VERSION 5.8 ;
BUSBITCHARS "[]" ;
DIVIDERCHAR "/" ;
UNITS
    DATABASE MICRONS 1000 ;
END UNITS

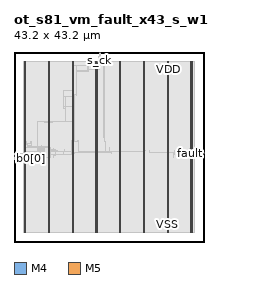
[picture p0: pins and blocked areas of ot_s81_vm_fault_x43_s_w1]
MACRO ot_s81_vm_fault_x43_s_w1
  FOREIGN ot_s81_vm_fault_x43_s_w1 0 0 ;
  CLASS BLOCK ;
  SIZE 43.2 BY 43.2 ;
  PIN b0[0]
    DIRECTION INPUT ;
    USE SIGNAL ;
    PORT
      LAYER M4 ;
        RECT  0 19.056 0.084 19.08 ;
    END
  END b0[0]
  PIN b0[1]
    DIRECTION INPUT ;
    USE SIGNAL ;
    PORT
      LAYER M4 ;
        RECT  0 19.152 0.084 19.176 ;
    END
  END b0[1]
  PIN b2[0]
    DIRECTION INPUT ;
    USE SIGNAL ;
    PORT
      LAYER M4 ;
        RECT  0 19.248 0.084 19.272 ;
    END
  END b2[0]
  PIN b2[1]
    DIRECTION INPUT ;
    USE SIGNAL ;
    PORT
      LAYER M4 ;
        RECT  0 19.344 0.084 19.368 ;
    END
  END b2[1]
  PIN b3[0]
    DIRECTION INPUT ;
    USE SIGNAL ;
    PORT
      LAYER M4 ;
        RECT  0 19.44 0.084 19.464 ;
    END
  END b3[0]
  PIN b3[1]
    DIRECTION INPUT ;
    USE SIGNAL ;
    PORT
      LAYER M4 ;
        RECT  0 19.536 0.084 19.56 ;
    END
  END b3[1]
  PIN bpar[0]
    DIRECTION INPUT ;
    USE SIGNAL ;
    PORT
      LAYER M4 ;
        RECT  0 19.632 0.084 19.656 ;
    END
  END bpar[0]
  PIN bpar[1]
    DIRECTION INPUT ;
    USE SIGNAL ;
    PORT
      LAYER M4 ;
        RECT  0 19.728 0.084 19.752 ;
    END
  END bpar[1]
  PIN bpar[2]
    DIRECTION INPUT ;
    USE SIGNAL ;
    PORT
      LAYER M4 ;
        RECT  0 19.824 0.084 19.848 ;
    END
  END bpar[2]
  PIN fault
    DIRECTION OUTPUT ;
    USE SIGNAL ;
    PORT
      LAYER M4 ;
        RECT  43.116 20.208 43.2 20.232 ;
    END
  END fault
  PIN o_d
    DIRECTION OUTPUT ;
    USE SIGNAL ;
    PORT
      LAYER M4 ;
        RECT  43.116 20.304 43.2 20.328 ;
    END
  END o_d
  PIN o_v
    DIRECTION OUTPUT ;
    USE SIGNAL ;
    PORT
      LAYER M4 ;
        RECT  43.116 20.4 43.2 20.424 ;
    END
  END o_v
  PIN ph1_bad
    DIRECTION INPUT ;
    USE SIGNAL ;
    PORT
      LAYER M4 ;
        RECT  0 19.92 0.084 19.944 ;
    END
  END ph1_bad
  PIN s_ck
    DIRECTION INPUT ;
    USE SIGNAL ;
    PORT
      LAYER M5 ;
        RECT  19.44 43.116 19.464 43.2 ;
    END
  END s_ck
  PIN s_rst_n
    DIRECTION INPUT ;
    USE SIGNAL ;
    PORT
      LAYER M5 ;
        RECT  19.536 43.116 19.56 43.2 ;
    END
  END s_rst_n
  PIN t_mark
    DIRECTION INPUT ;
    USE SIGNAL ;
    PORT
      LAYER M4 ;
        RECT  0 20.016 0.084 20.04 ;
    END
  END t_mark
  PIN VDD
    DIRECTION INOUT ;
    USE POWER ;
    PORT
      LAYER M5 ;
        RECT  40.392 2.151 40.512 41.049 ;
        RECT  34.992 2.151 35.112 41.049 ;
        RECT  29.592 2.151 29.712 41.049 ;
        RECT  24.192 2.151 24.312 41.049 ;
        RECT  18.792 2.151 18.912 41.049 ;
        RECT  13.392 2.151 13.512 41.049 ;
        RECT  7.992 2.151 8.112 41.049 ;
        RECT  2.592 2.151 2.712 41.049 ;
    END
  END VDD
  PIN VSS
    DIRECTION INOUT ;
    USE GROUND ;
    PORT
      LAYER M5 ;
        RECT  40.2 2.137 40.32 41.063 ;
        RECT  34.8 2.137 34.92 41.063 ;
        RECT  29.4 2.137 29.52 41.063 ;
        RECT  24 2.137 24.12 41.063 ;
        RECT  18.6 2.137 18.72 41.063 ;
        RECT  13.2 2.137 13.32 41.063 ;
        RECT  7.8 2.137 7.92 41.063 ;
        RECT  2.4 2.137 2.52 41.063 ;
    END
  END VSS
  # OT_OBS_CLOSED layer=M5 d_um=1.536 added=3
  OBS
    LAYER RVTN ;
     RECT  2.16 2.16 41.04 2.295 ;
     RECT  2.16 2.565 41.04 2.835 ;
     RECT  2.16 3.105 41.04 3.375 ;
     RECT  2.16 3.645 41.04 3.915 ;
     RECT  2.16 4.185 41.04 4.455 ;
     RECT  2.16 4.725 41.04 4.995 ;
     RECT  2.16 5.265 41.04 5.535 ;
     RECT  2.16 5.805 41.04 6.075 ;
     RECT  2.16 6.345 41.04 6.615 ;
     RECT  2.16 6.885 41.04 7.155 ;
     RECT  2.16 7.425 41.04 7.695 ;
     RECT  2.16 7.965 41.04 8.235 ;
     RECT  2.16 8.505 41.04 8.775 ;
     RECT  2.16 9.045 41.04 9.315 ;
     RECT  2.16 9.585 41.04 9.855 ;
     RECT  2.16 10.125 41.04 10.395 ;
     RECT  2.16 10.665 41.04 10.935 ;
     RECT  2.16 11.205 41.04 11.475 ;
     RECT  2.16 11.745 41.04 12.015 ;
     RECT  2.16 12.285 41.04 12.555 ;
     RECT  2.16 12.825 41.04 13.095 ;
     RECT  2.16 13.365 41.04 13.635 ;
     RECT  2.16 13.905 41.04 14.175 ;
     RECT  2.16 14.445 41.04 14.715 ;
     RECT  2.16 14.985 41.04 15.255 ;
     RECT  2.16 15.525 41.04 15.795 ;
     RECT  2.16 16.065 41.04 16.335 ;
     RECT  2.16 16.605 41.04 16.875 ;
     RECT  2.16 17.145 41.04 17.415 ;
     RECT  2.16 17.685 41.04 17.955 ;
     RECT  2.16 18.225 41.04 18.495 ;
     RECT  2.16 18.765 41.04 19.035 ;
     RECT  2.16 19.305 41.04 19.575 ;
     RECT  2.16 19.845 41.04 20.115 ;
     RECT  2.16 20.385 41.04 20.655 ;
     RECT  2.16 20.925 41.04 21.195 ;
     RECT  2.16 21.465 41.04 21.735 ;
     RECT  2.16 22.005 41.04 22.275 ;
     RECT  2.16 22.545 41.04 22.815 ;
     RECT  2.16 23.085 41.04 23.355 ;
     RECT  2.16 23.625 41.04 23.895 ;
     RECT  2.16 24.165 41.04 24.435 ;
     RECT  2.16 24.705 41.04 24.975 ;
     RECT  2.16 25.245 41.04 25.515 ;
     RECT  2.16 25.785 41.04 26.055 ;
     RECT  2.16 26.325 41.04 26.595 ;
     RECT  2.16 26.865 41.04 27.135 ;
     RECT  2.16 27.405 41.04 27.675 ;
     RECT  2.16 27.945 41.04 28.215 ;
     RECT  2.16 28.485 41.04 28.755 ;
     RECT  2.16 29.025 41.04 29.295 ;
     RECT  2.16 29.565 41.04 29.835 ;
     RECT  2.16 30.105 41.04 30.375 ;
     RECT  2.16 30.645 41.04 30.915 ;
     RECT  2.16 31.185 41.04 31.455 ;
     RECT  2.16 31.725 41.04 31.995 ;
     RECT  2.16 32.265 41.04 32.535 ;
     RECT  2.16 32.805 41.04 33.075 ;
     RECT  2.16 33.345 41.04 33.615 ;
     RECT  2.16 33.885 41.04 34.155 ;
     RECT  2.16 34.425 41.04 34.695 ;
     RECT  2.16 34.965 41.04 35.235 ;
     RECT  2.16 35.505 41.04 35.775 ;
     RECT  2.16 36.045 41.04 36.315 ;
     RECT  2.16 36.585 41.04 36.855 ;
     RECT  2.16 37.125 41.04 37.395 ;
     RECT  2.16 37.665 41.04 37.935 ;
     RECT  2.16 38.205 41.04 38.475 ;
     RECT  2.16 38.745 41.04 39.015 ;
     RECT  2.16 39.285 41.04 39.555 ;
     RECT  2.16 39.825 41.04 40.095 ;
     RECT  2.16 40.365 41.04 40.635 ;
     RECT  2.16 40.905 41.04 41.04 ;
    LAYER RVTP ;
     RECT  2.16 2.295 41.04 2.565 ;
     RECT  2.16 2.835 41.04 3.105 ;
     RECT  2.16 3.375 41.04 3.645 ;
     RECT  2.16 3.915 41.04 4.185 ;
     RECT  2.16 4.455 41.04 4.725 ;
     RECT  2.16 4.995 41.04 5.265 ;
     RECT  2.16 5.535 41.04 5.805 ;
     RECT  2.16 6.075 41.04 6.345 ;
     RECT  2.16 6.615 41.04 6.885 ;
     RECT  2.16 7.155 41.04 7.425 ;
     RECT  2.16 7.695 41.04 7.965 ;
     RECT  2.16 8.235 41.04 8.505 ;
     RECT  2.16 8.775 41.04 9.045 ;
     RECT  2.16 9.315 41.04 9.585 ;
     RECT  2.16 9.855 41.04 10.125 ;
     RECT  2.16 10.395 41.04 10.665 ;
     RECT  2.16 10.935 41.04 11.205 ;
     RECT  2.16 11.475 41.04 11.745 ;
     RECT  2.16 12.015 41.04 12.285 ;
     RECT  2.16 12.555 41.04 12.825 ;
     RECT  2.16 13.095 41.04 13.365 ;
     RECT  2.16 13.635 41.04 13.905 ;
     RECT  2.16 14.175 41.04 14.445 ;
     RECT  2.16 14.715 41.04 14.985 ;
     RECT  2.16 15.255 41.04 15.525 ;
     RECT  2.16 15.795 41.04 16.065 ;
     RECT  2.16 16.335 41.04 16.605 ;
     RECT  2.16 16.875 41.04 17.145 ;
     RECT  2.16 17.415 41.04 17.685 ;
     RECT  2.16 17.955 41.04 18.225 ;
     RECT  2.16 18.495 41.04 18.765 ;
     RECT  2.16 19.035 41.04 19.305 ;
     RECT  2.16 19.575 41.04 19.845 ;
     RECT  2.16 20.115 41.04 20.385 ;
     RECT  2.16 20.655 41.04 20.925 ;
     RECT  2.16 21.195 41.04 21.465 ;
     RECT  2.16 21.735 41.04 22.005 ;
     RECT  2.16 22.275 41.04 22.545 ;
     RECT  2.16 22.815 41.04 23.085 ;
     RECT  2.16 23.355 41.04 23.625 ;
     RECT  2.16 23.895 41.04 24.165 ;
     RECT  2.16 24.435 41.04 24.705 ;
     RECT  2.16 24.975 41.04 25.245 ;
     RECT  2.16 25.515 41.04 25.785 ;
     RECT  2.16 26.055 41.04 26.325 ;
     RECT  2.16 26.595 41.04 26.865 ;
     RECT  2.16 27.135 41.04 27.405 ;
     RECT  2.16 27.675 41.04 27.945 ;
     RECT  2.16 28.215 41.04 28.485 ;
     RECT  2.16 28.755 41.04 29.025 ;
     RECT  2.16 29.295 41.04 29.565 ;
     RECT  2.16 29.835 41.04 30.105 ;
     RECT  2.16 30.375 41.04 30.645 ;
     RECT  2.16 30.915 41.04 31.185 ;
     RECT  2.16 31.455 41.04 31.725 ;
     RECT  2.16 31.995 41.04 32.265 ;
     RECT  2.16 32.535 41.04 32.805 ;
     RECT  2.16 33.075 41.04 33.345 ;
     RECT  2.16 33.615 41.04 33.885 ;
     RECT  2.16 34.155 41.04 34.425 ;
     RECT  2.16 34.695 41.04 34.965 ;
     RECT  2.16 35.235 41.04 35.505 ;
     RECT  2.16 35.775 41.04 36.045 ;
     RECT  2.16 36.315 41.04 36.585 ;
     RECT  2.16 36.855 41.04 37.125 ;
     RECT  2.16 37.395 41.04 37.665 ;
     RECT  2.16 37.935 41.04 38.205 ;
     RECT  2.16 38.475 41.04 38.745 ;
     RECT  2.16 39.015 41.04 39.285 ;
     RECT  2.16 39.555 41.04 39.825 ;
     RECT  2.16 40.095 41.04 40.365 ;
     RECT  2.16 40.635 41.04 40.905 ;
    LAYER M1 ;
     RECT  2.16 2.151 41.04 41.049 ;
    LAYER M2 ;
     RECT  0.103 18.774 2.16 18.792 ;
     RECT  2.16 2.151 41.04 41.049 ;
     RECT  41.04 19.926 42.143 20.844 ;
     RECT  42.143 20.826 42.179 20.844 ;
     RECT  42.143 19.926 42.215 19.944 ;
    LAYER M3 ;
     RECT  2.415 2.143 2.505 2.413 ;
     RECT  7.815 2.143 7.905 2.413 ;
     RECT  13.215 2.143 13.305 2.413 ;
     RECT  18.615 2.143 18.705 2.413 ;
     RECT  24.015 2.143 24.105 2.413 ;
     RECT  29.415 2.143 29.505 2.413 ;
     RECT  34.815 2.143 34.905 2.413 ;
     RECT  40.215 2.143 40.305 2.413 ;
     RECT  3.888 18.391 3.906 18.571 ;
     RECT  5.076 18.565 5.094 18.571 ;
     RECT  3.852 18.571 5.742 18.661 ;
     RECT  2.415 2.413 2.697 18.76 ;
     RECT  3.492 18.661 5.742 18.76 ;
     RECT  2.415 18.76 5.742 19.039 ;
     RECT  2.415 19.039 5.85 19.075 ;
     RECT  0.108 18.769 0.126 19.085 ;
     RECT  2.304 19.075 5.85 19.111 ;
     RECT  2.304 19.111 5.958 19.237 ;
     RECT  6.84 19.111 6.858 19.237 ;
     RECT  7.815 2.413 8.097 19.273 ;
     RECT  2.304 19.237 6.966 19.381 ;
     RECT  7.704 19.273 8.097 19.381 ;
     RECT  2.304 19.381 8.19 19.499 ;
     RECT  7.704 19.499 8.19 19.535 ;
     RECT  9.072 19.237 9.09 19.741 ;
     RECT  2.304 19.499 6.966 19.769 ;
     RECT  36.324 19.111 36.342 19.813 ;
     RECT  6.516 19.769 6.966 19.853 ;
     RECT  40.215 2.413 40.497 19.885 ;
     RECT  2.304 19.769 5.742 19.912 ;
     RECT  7.815 19.535 8.19 19.921 ;
     RECT  8.964 19.741 9.486 19.921 ;
     RECT  2.268 19.912 5.742 19.949 ;
     RECT  13.215 2.413 13.497 19.963 ;
     RECT  13.104 19.963 13.497 20.083 ;
     RECT  13.104 20.083 13.59 20.119 ;
     RECT  0.108 20.011 0.126 20.141 ;
     RECT  37.404 19.921 37.422 20.155 ;
     RECT  39.636 19.885 40.497 20.155 ;
     RECT  12.06 20.119 13.59 20.191 ;
     RECT  42.192 19.921 42.21 20.191 ;
     RECT  42.12 20.191 42.21 20.237 ;
     RECT  36.324 19.813 36.522 20.299 ;
     RECT  37.404 20.155 38.502 20.299 ;
     RECT  12.06 20.191 13.662 20.309 ;
     RECT  39.636 20.155 40.698 20.309 ;
     RECT  11.304 19.921 11.322 20.317 ;
     RECT  36.144 20.299 38.502 20.345 ;
     RECT  22.14 20.155 22.158 20.347 ;
     RECT  20.736 20.353 21.078 20.389 ;
     RECT  21.888 20.347 22.158 20.389 ;
     RECT  36.504 20.345 38.502 20.425 ;
     RECT  42.12 20.237 42.174 20.429 ;
     RECT  20.736 20.389 22.158 20.453 ;
     RECT  21.78 20.453 22.158 20.461 ;
     RECT  36.504 20.425 38.754 20.461 ;
     RECT  39.924 20.309 40.698 20.461 ;
     RECT  7.815 19.921 9.486 20.551 ;
     RECT  11.16 20.317 11.322 20.551 ;
     RECT  12.06 20.309 12.114 20.551 ;
     RECT  13.215 20.309 13.662 20.551 ;
     RECT  29.415 2.413 29.697 20.551 ;
     RECT  36.504 20.461 39.15 20.573 ;
     RECT  11.16 20.551 12.114 20.579 ;
     RECT  39.924 20.461 40.734 20.579 ;
     RECT  2.304 19.949 5.742 20.587 ;
     RECT  6.516 19.853 6.894 20.587 ;
     RECT  7.815 20.551 9.882 20.587 ;
     RECT  2.304 20.587 9.882 20.615 ;
     RECT  37.62 20.573 39.15 20.615 ;
     RECT  21.78 20.461 22.23 20.651 ;
     RECT  11.16 20.579 11.43 20.669 ;
     RECT  13.215 20.551 13.914 20.669 ;
     RECT  37.944 20.615 39.15 20.687 ;
     RECT  29.415 20.551 29.754 20.731 ;
     RECT  30.744 20.299 30.762 20.759 ;
     RECT  36.504 20.573 36.522 20.759 ;
     RECT  2.34 20.615 9.882 20.849 ;
     RECT  29.415 20.731 29.934 20.849 ;
     RECT  39.924 20.579 40.626 20.849 ;
     RECT  42.156 20.429 42.174 20.849 ;
     RECT  2.34 20.849 9.378 20.885 ;
     RECT  37.944 20.687 38.754 20.885 ;
     RECT  2.376 20.885 9.378 20.921 ;
     RECT  38.484 20.885 38.502 20.921 ;
     RECT  9.072 20.921 9.378 21.029 ;
     RECT  11.412 20.669 11.43 21.029 ;
     RECT  39.996 20.849 40.626 21.119 ;
     RECT  2.376 20.921 8.097 21.155 ;
     RECT  39.996 21.119 40.497 21.155 ;
     RECT  9.072 21.029 9.09 21.227 ;
     RECT  21.78 20.651 21.798 21.425 ;
     RECT  2.415 21.155 8.097 21.659 ;
     RECT  2.415 21.659 5.274 21.695 ;
     RECT  6.228 21.659 8.097 21.695 ;
     RECT  6.228 21.695 6.786 21.731 ;
     RECT  2.415 21.695 4.626 21.767 ;
     RECT  6.228 21.731 6.246 21.839 ;
     RECT  2.415 21.767 4.086 21.965 ;
     RECT  2.415 21.965 4.014 22.505 ;
     RECT  3.672 22.505 4.014 22.577 ;
     RECT  3.672 22.577 3.906 22.649 ;
     RECT  2.415 22.505 2.934 22.739 ;
     RECT  3.672 22.649 3.87 22.739 ;
     RECT  20.736 20.453 20.754 22.739 ;
     RECT  14.328 22.795 14.562 23.009 ;
     RECT  20.484 22.783 20.502 23.549 ;
     RECT  7.815 21.695 8.097 27.301 ;
     RECT  8.82 27.163 8.838 27.301 ;
     RECT  7.815 27.301 8.838 27.329 ;
     RECT  6.84 27.163 6.858 27.341 ;
     RECT  7.815 27.329 8.622 27.341 ;
     RECT  11.736 30.283 11.754 30.415 ;
     RECT  11.34 30.415 11.754 30.712 ;
     RECT  11.16 30.712 11.754 30.749 ;
     RECT  13.215 20.669 13.497 33.067 ;
     RECT  13.215 33.067 13.662 33.269 ;
     RECT  14.22 33.421 14.238 33.539 ;
     RECT  13.215 33.269 13.497 34.591 ;
     RECT  14.256 34.363 14.274 34.591 ;
     RECT  13.215 34.591 14.274 34.619 ;
     RECT  13.215 34.619 13.986 34.781 ;
     RECT  16.92 38.779 16.938 38.923 ;
     RECT  16.704 38.923 16.938 38.939 ;
     RECT  16.704 38.939 16.722 39.245 ;
     RECT  20.448 23.701 20.466 40.019 ;
     RECT  18.615 2.413 18.897 40.027 ;
     RECT  18.615 40.027 19.53 40.171 ;
     RECT  18.615 40.171 19.71 40.559 ;
     RECT  2.415 22.739 2.697 40.787 ;
     RECT  7.815 27.341 8.097 40.787 ;
     RECT  13.215 34.781 13.497 40.787 ;
     RECT  24.015 2.413 24.297 40.787 ;
     RECT  29.415 20.849 29.697 40.787 ;
     RECT  34.815 2.413 35.097 40.787 ;
     RECT  40.215 21.155 40.497 40.787 ;
     RECT  18.615 40.559 19.494 40.829 ;
     RECT  2.415 40.787 2.505 41.057 ;
     RECT  7.815 40.787 7.905 41.057 ;
     RECT  13.215 40.787 13.305 41.057 ;
     RECT  18.615 40.829 19.314 41.057 ;
     RECT  24.015 40.787 24.105 41.057 ;
     RECT  29.415 40.787 29.505 41.057 ;
     RECT  34.815 40.787 34.905 41.057 ;
     RECT  40.215 40.787 40.305 41.057 ;
     RECT  19.296 41.057 19.314 42.221 ;
    LAYER M4 ;
     RECT  0.084 19.056 0.097 19.08 ;
     RECT  0.06 19.08 0.097 19.152 ;
     RECT  0.084 19.152 0.097 19.176 ;
     RECT  0.06 19.176 0.097 19.248 ;
     RECT  0.084 19.248 0.097 19.272 ;
     RECT  0.06 19.272 0.097 19.344 ;
     RECT  0.084 19.344 0.097 19.368 ;
     RECT  0.06 19.368 0.097 19.44 ;
     RECT  0.084 19.44 0.097 19.464 ;
     RECT  0.06 19.464 0.097 19.536 ;
     RECT  0.084 19.536 0.097 19.56 ;
     RECT  0.06 19.56 0.097 19.632 ;
     RECT  0.084 19.632 0.097 19.656 ;
     RECT  0.06 19.656 0.097 19.728 ;
     RECT  0.084 19.728 0.097 19.752 ;
     RECT  0.06 19.752 0.097 19.824 ;
     RECT  0.084 19.824 0.097 19.848 ;
     RECT  0.06 19.848 0.097 19.92 ;
     RECT  0.084 19.92 0.097 19.944 ;
     RECT  0.06 19.944 0.097 20.016 ;
     RECT  0.084 20.016 0.097 20.04 ;
     RECT  0.097 19.056 0.137 20.136 ;
     RECT  0.137 19.152 2.408 20.136 ;
     RECT  2.408 2.148 2.512 41.052 ;
     RECT  2.512 2.418 2.704 40.782 ;
     RECT  2.704 19.92 3.059 22.2 ;
     RECT  2.704 18.768 3.395 18.792 ;
     RECT  4.165 18.624 4.345 18.648 ;
     RECT  3.059 19.92 4.489 21.48 ;
     RECT  4.489 19.632 4.597 21.48 ;
     RECT  4.597 19.632 4.681 21.672 ;
     RECT  4.345 18.576 4.738 18.648 ;
     RECT  4.681 19.632 4.738 21.48 ;
     RECT  4.738 18.576 4.853 21.48 ;
     RECT  4.853 19.632 4.997 21.48 ;
     RECT  4.853 18.576 5.123 18.648 ;
     RECT  4.997 19.632 5.177 21.384 ;
     RECT  5.123 18.624 5.393 18.648 ;
     RECT  5.177 19.728 5.437 21.384 ;
     RECT  5.437 21.36 6.577 21.384 ;
     RECT  5.437 19.728 6.649 20.376 ;
     RECT  6.577 21.36 6.649 21.432 ;
     RECT  5.365 27.312 6.829 27.336 ;
     RECT  6.649 19.728 6.937 21.432 ;
     RECT  6.937 19.248 7.808 21.432 ;
     RECT  6.829 27.168 7.808 27.336 ;
     RECT  7.808 2.148 7.912 41.052 ;
     RECT  7.912 2.418 8.104 40.782 ;
     RECT  8.104 19.248 8.243 21.432 ;
     RECT  8.104 27.168 8.849 27.336 ;
     RECT  8.243 19.824 9.497 20.568 ;
     RECT  9.497 19.968 11.149 20.568 ;
     RECT  11.149 30.72 11.701 30.744 ;
     RECT  8.849 27.312 11.747 27.336 ;
     RECT  11.701 30.288 11.788 30.744 ;
     RECT  11.788 30.72 11.809 30.744 ;
     RECT  11.149 19.968 13.208 20.664 ;
     RECT  13.093 23.04 13.208 23.064 ;
     RECT  11.749 33.072 13.208 33.096 ;
     RECT  11.173 34.368 13.208 34.392 ;
     RECT  13.208 2.148 13.312 41.052 ;
     RECT  13.312 2.418 13.504 40.782 ;
     RECT  13.504 22.8 13.667 23.064 ;
     RECT  13.504 33.072 13.673 34.776 ;
     RECT  13.504 20.208 13.715 20.664 ;
     RECT  13.715 20.352 13.925 20.664 ;
     RECT  13.673 33.456 14.041 34.776 ;
     RECT  14.041 33.456 14.284 34.392 ;
     RECT  14.284 34.368 14.285 34.392 ;
     RECT  13.667 22.8 14.617 22.824 ;
     RECT  13.504 38.784 16.693 38.952 ;
     RECT  13.504 40.032 16.693 40.056 ;
     RECT  16.693 38.784 16.949 40.056 ;
     RECT  13.925 20.352 18.608 20.616 ;
     RECT  16.949 39.216 18.608 40.056 ;
     RECT  18.608 2.148 18.712 41.052 ;
     RECT  18.712 2.418 18.904 40.782 ;
     RECT  18.904 39.216 19.475 40.056 ;
     RECT  19.475 40.032 19.541 40.056 ;
     RECT  19.285 42.192 19.571 42.216 ;
     RECT  18.904 20.352 21.917 20.616 ;
     RECT  21.917 20.592 24.008 20.616 ;
     RECT  24.008 2.148 24.112 41.052 ;
     RECT  24.112 2.418 24.304 40.782 ;
     RECT  24.304 20.592 29.408 20.616 ;
     RECT  29.408 2.148 29.512 41.052 ;
     RECT  29.512 2.418 29.704 40.782 ;
     RECT  29.704 20.592 29.765 20.616 ;
     RECT  30.733 20.304 34.808 20.328 ;
     RECT  34.808 2.148 34.912 41.052 ;
     RECT  34.912 2.418 35.104 40.782 ;
     RECT  35.104 20.304 37.213 20.328 ;
     RECT  37.213 20.304 37.253 20.568 ;
     RECT  37.253 20.544 37.973 20.568 ;
     RECT  40.208 2.148 40.312 41.052 ;
     RECT  40.312 2.418 40.504 40.782 ;
     RECT  42.109 20.4 42.145 20.424 ;
     RECT  42.145 20.304 42.181 20.424 ;
     RECT  42.181 20.208 43.116 20.232 ;
     RECT  42.181 20.232 43.164 20.304 ;
     RECT  42.181 20.304 43.116 20.328 ;
     RECT  42.181 20.328 43.164 20.4 ;
     RECT  42.181 20.4 43.116 20.424 ;
    LAYER M5 ;
     RECT  2.4 2.137 2.52 2.151 ;
     RECT  7.8 2.137 7.92 2.151 ;
     RECT  13.2 2.137 13.32 2.151 ;
     RECT  18.6 2.137 18.72 2.151 ;
     RECT  24 2.137 24.12 2.151 ;
     RECT  29.4 2.137 29.52 2.151 ;
     RECT  34.8 2.137 34.92 2.151 ;
     RECT  40.2 2.137 40.32 2.151 ;
     RECT  4.704 18.565 5.112 18.613 ;
     RECT  2.4 2.151 2.712 18.757 ;
     RECT  4.176 18.613 5.112 18.757 ;
     RECT  7.8 2.151 8.112 19.237 ;
     RECT  13.2 2.151 13.512 20.149 ;
     RECT  13.104 20.149 13.512 20.197 ;
     RECT  13.104 20.197 13.704 20.341 ;
     RECT  2.4 18.757 5.112 20.485 ;
     RECT  7.8 19.237 8.232 21.443 ;
     RECT  2.4 20.485 5.4 21.491 ;
     RECT  4.608 21.491 5.4 21.683 ;
     RECT  2.4 21.491 3.048 22.211 ;
     RECT  13.104 20.341 14.568 22.835 ;
     RECT  13.104 22.835 13.656 23.075 ;
     RECT  5.376 21.683 5.4 27.347 ;
     RECT  11.712 27.301 11.736 30.709 ;
     RECT  11.184 30.709 11.784 33.107 ;
     RECT  13.2 23.075 13.656 33.445 ;
     RECT  11.184 33.107 11.208 34.403 ;
     RECT  18.6 2.151 18.912 39.205 ;
     RECT  13.2 33.445 14.232 40.067 ;
     RECT  2.4 22.211 2.712 41.049 ;
     RECT  7.8 21.443 8.112 41.049 ;
     RECT  13.2 40.067 13.512 41.049 ;
     RECT  24 2.151 24.312 41.049 ;
     RECT  29.4 2.151 29.712 41.049 ;
     RECT  34.8 2.151 35.112 41.049 ;
     RECT  40.2 2.151 40.512 41.049 ;
     RECT  2.4 41.049 2.52 41.063 ;
     RECT  7.8 41.049 7.92 41.063 ;
     RECT  13.2 41.049 13.32 41.063 ;
     RECT  18.6 39.205 19.464 41.063 ;
     RECT  24 41.049 24.12 41.063 ;
     RECT  29.4 41.049 29.52 41.063 ;
     RECT  34.8 41.049 34.92 41.063 ;
     RECT  40.2 41.049 40.32 41.063 ;
     RECT  19.44 41.063 19.464 42.181 ;
     RECT  19.44 42.181 19.56 43.116 ;
     RECT  19.464 43.116 19.536 43.152 ;
     RECT  2.712 18.613 4.176 18.757 ;
     RECT  11.736 27.301 13.2 30.709 ;
     RECT  11.784 30.709 13.2 33.107 ;
  END
END ot_s81_vm_fault_x43_s_w1
END LIBRARY
